VERSION 5.5 ;
NAMESCASESENSITIVE ON ;
BUSBITCHARS "[]" ;
DIVIDERCHAR "/" ;

PROPERTYDEFINITIONS
  LAYER routingPitch REAL ;
END PROPERTYDEFINITIONS

UNITS
  DATABASE MICRONS 1000 ;
END UNITS
MANUFACTURINGGRID 0.01 ;
LAYER POLY1
  TYPE MASTERSLICE ;
END POLY1

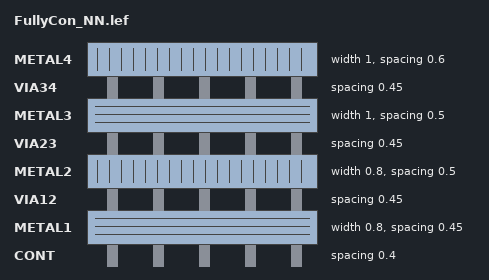
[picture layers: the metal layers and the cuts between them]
LAYER CONT
  TYPE CUT ;
  SPACING 0.4 ;
END CONT

LAYER METAL1
  TYPE ROUTING ;
  DIRECTION HORIZONTAL ;
  PITCH 0 ;
  WIDTH 0.8 ;
  SPACING 0.45 ;
  PROPERTY routingPitch 1.25 ;
END METAL1

LAYER VIA12
  TYPE CUT ;
  SPACING 0.45 ;
END VIA12

LAYER METAL2
  TYPE ROUTING ;
  DIRECTION VERTICAL ;
  PITCH 0 ;
  WIDTH 0.8 ;
  SPACING 0.5 ;
  PROPERTY routingPitch 1.4 ;
END METAL2

LAYER VIA23
  TYPE CUT ;
  SPACING 0.45 ;
END VIA23

LAYER METAL3
  TYPE ROUTING ;
  DIRECTION HORIZONTAL ;
  PITCH 0 ;
  WIDTH 1.0 ;
  SPACING 0.5 ;
  PROPERTY routingPitch 1.25 ;
END METAL3

LAYER VIA34
  TYPE CUT ;
  SPACING 0.45 ;
END VIA34

LAYER METAL4
  TYPE ROUTING ;
  DIRECTION VERTICAL ;
  PITCH 0 ;
  WIDTH 1.0 ;
  SPACING 0.6 ;
  PROPERTY routingPitch 1.4 ;
END METAL4

LAYER OVERLAP
  TYPE OVERLAP ;
END OVERLAP

VIARULE M4_M3 GENERATE
  LAYER METAL3 ;
    ENCLOSURE 0.2 0.2 ;
  LAYER METAL4 ;
    ENCLOSURE 0.15 0.15 ;
  LAYER VIA34 ;
    RECT -0.25 -0.25 0.25 0.25 ;
    SPACING 1 BY 1 ;
END M4_M3

VIARULE M3_M2 GENERATE
  LAYER METAL2 ;
    ENCLOSURE 0.2 0.2 ;
  LAYER METAL3 ;
    ENCLOSURE 0.15 0.15 ;
  LAYER VIA23 ;
    RECT -0.25 -0.25 0.25 0.25 ;
    SPACING 1 BY 1 ;
END M3_M2

VIARULE M2_M1 GENERATE
  LAYER METAL1 ;
    ENCLOSURE 0.2 0.2 ;
  LAYER METAL2 ;
    ENCLOSURE 0.15 0.15 ;
  LAYER VIA12 ;
    RECT -0.25 -0.25 0.25 0.25 ;
    SPACING 1 BY 1 ;
END M2_M1

VIARULE M1_POLY1 GENERATE
  LAYER POLY1 ;
    ENCLOSURE 0.2 0.2 ;
  LAYER METAL1 ;
    ENCLOSURE 0.15 0.15 ;
  LAYER CONT ;
    RECT -0.2 -0.2 0.2 0.2 ;
    SPACING 1 BY 1 ;
END M1_POLY1

VIA M1_POLY1
  LAYER CONT ;
    RECT -0.2 -0.2 0.2 0.2 ;
  LAYER POLY1 ;
    RECT -0.4 -0.4 0.4 0.4 ;
  LAYER METAL1 ;
    RECT -0.35 -0.35 0.35 0.35 ;
END M1_POLY1

VIA M2_M1
  LAYER VIA12 ;
    RECT -0.25 -0.25 0.25 0.25 ;
  LAYER METAL2 ;
    RECT -0.4 -0.4 0.4 0.4 ;
  LAYER METAL1 ;
    RECT -0.45 -0.45 0.45 0.45 ;
END M2_M1

VIA M3_M2
  LAYER VIA23 ;
    RECT -0.25 -0.25 0.25 0.25 ;
  LAYER METAL3 ;
    RECT -0.4 -0.4 0.4 0.4 ;
  LAYER METAL2 ;
    RECT -0.45 -0.45 0.45 0.45 ;
END M3_M2

VIA M4_M3
  LAYER VIA34 ;
    RECT -0.25 -0.25 0.25 0.25 ;
  LAYER METAL4 ;
    RECT -0.4 -0.4 0.4 0.4 ;
  LAYER METAL3 ;
    RECT -0.45 -0.45 0.45 0.45 ;
END M4_M3


MACRO TSMC350nm_VinjDecode2to4_vtile_spacing
END TSMC350nm_VinjDecode2to4_vtile_spacing

MACRO TSMC350nm_VinjDecode2to4_vtile_bridge_spacing
END TSMC350nm_VinjDecode2to4_vtile_bridge_spacing

MACRO TSMC350nm_VinjDecode2to4_vtile_D_bridge
END TSMC350nm_VinjDecode2to4_vtile_D_bridge

MACRO TSMC350nm_VinjDecode2to4_vtile
  PIN Vinj
    DIRECTION INOUT ;
    USE SIGNAL ;
    PORT
      LAYER METAL1 ;
        RECT 7.78 11.04 9.06 11.45 ;
    END
  END Vinj
  PIN OUT<0>
    DIRECTION INOUT ;
    USE SIGNAL ;
    PORT
      LAYER METAL1 ;
        RECT 19.66 18.91 20.11 19.59 ;
    END
  END OUT<0>
  PIN OUT<1>
    DIRECTION INOUT ;
    USE SIGNAL ;
    PORT
      LAYER METAL1 ;
        RECT 19.66 13.41 20.12 14.1 ;
    END
  END OUT<1>
  PIN OUT<2>
    DIRECTION INOUT ;
    USE SIGNAL ;
    PORT
      LAYER METAL1 ;
        RECT 19.66 7.92 20.11 8.59 ;
    END
  END OUT<2>
  PIN OUT<3>
    DIRECTION INOUT ;
    USE SIGNAL ;
    PORT
      LAYER METAL1 ;
        RECT 19.66 2.41 20.11 3.09 ;
    END
  END OUT<3>
  PIN ENABLE
    DIRECTION INOUT ;
    USE SIGNAL ;
    PORT
      LAYER METAL1 ;
        RECT 0.01 3.48 0.71 4.21 ;
    END
  END ENABLE
  PIN GND
    DIRECTION INOUT ;
    USE SIGNAL ;
    PORT
      LAYER METAL1 ;
        RECT 19.52 5.0 20.12 5.99 ;
    END
  END GND
  PIN VINJ
    DIRECTION INOUT ;
    USE SIGNAL ;
    PORT
      LAYER METAL1 ;
        RECT 19.15 21.56 20.05 21.96 ;
    END
  END VINJ
  PIN IN<1>
    DIRECTION INOUT ;
    USE SIGNAL ;
    PORT
      LAYER METAL2 ;
        RECT 6.56 20.89 7.5 22.0 ;
    END
  END IN<1>
  PIN IN<0>
    DIRECTION INOUT ;
    USE SIGNAL ;
    PORT
      LAYER METAL2 ;
        RECT 3.9 20.96 4.5 22.0 ;
    END
  END IN<0>
END TSMC350nm_VinjDecode2to4_vtile

MACRO TSMC350nm_VinjDecode2to4_vtile_C_bridge
END TSMC350nm_VinjDecode2to4_vtile_C_bridge

MACRO TSMC350nm_VinjDecode2to4_vtile_B_bridge
END TSMC350nm_VinjDecode2to4_vtile_B_bridge

MACRO TSMC350nm_VinjDecode2to4_vtile_A_bridge
END TSMC350nm_VinjDecode2to4_vtile_A_bridge

MACRO TSMC350nm_drainSelect_progrundrains
  PIN prog_drain<3>
    DIRECTION INOUT ;
    USE SIGNAL ;
    PORT
      LAYER METAL1 ;
        RECT 30.93 0.93 31.86 1.43 ;
    END
  END prog_drain<3>
  PIN prog_drain<2>
    DIRECTION INOUT ;
    USE SIGNAL ;
    PORT
      LAYER METAL1 ;
        RECT 30.97 9.62 31.86 10.12 ;
    END
  END prog_drain<2>
  PIN prog_drain<1>
    DIRECTION INOUT ;
    USE SIGNAL ;
    PORT
      LAYER METAL1 ;
        RECT 31.0 13.97 31.86 14.47 ;
    END
  END prog_drain<1>
  PIN run_drain<3>
    DIRECTION INOUT ;
    USE SIGNAL ;
    PORT
      LAYER METAL1 ;
        RECT 31.01 2.45 31.86 2.95 ;
    END
  END run_drain<3>
  PIN run_drain<2>
    DIRECTION INOUT ;
    USE SIGNAL ;
    PORT
      LAYER METAL1 ;
        RECT 30.94 5.31 31.86 5.81 ;
    END
  END run_drain<2>
  PIN prog_drain<0>
    DIRECTION INOUT ;
    USE SIGNAL ;
    PORT
      LAYER METAL1 ;
        RECT 31.12 20.75 31.86 21.25 ;
    END
  END prog_drain<0>
  PIN GND
    DIRECTION INOUT ;
    USE SIGNAL ;
    PORT
      LAYER METAL2 ;
        RECT 4.19 21.33 4.99 22.0 ;
    END
  END GND
  PIN VINJ
    DIRECTION INOUT ;
    USE SIGNAL ;
    PORT
      LAYER METAL1 ;
        RECT 1.4 21.5 2.8 22.0 ;
    END
  END VINJ
  PIN run_drain<0>
    DIRECTION INOUT ;
    USE SIGNAL ;
    PORT
      LAYER METAL1 ;
        RECT 31.01 19.56 31.86 20.06 ;
    END
  END run_drain<0>
  PIN run_drain<1>
    DIRECTION INOUT ;
    USE SIGNAL ;
    PORT
      LAYER METAL1 ;
        RECT 31.04 16.75 31.86 17.24 ;
    END
  END run_drain<1>
  PIN SELECT<3>
    DIRECTION INOUT ;
    USE SIGNAL ;
    PORT
      LAYER METAL1 ;
        RECT 0.0 2.54 0.67 2.97 ;
    END
  END SELECT<3>
  PIN SELET<2>
    DIRECTION INOUT ;
    USE SIGNAL ;
    PORT
      LAYER METAL1 ;
        RECT 0.0 8.03 0.67 8.46 ;
    END
  END SELET<2>
  PIN SELECT<1>
    DIRECTION INOUT ;
    USE SIGNAL ;
    PORT
      LAYER METAL1 ;
        RECT 0.0 13.54 0.67 13.97 ;
    END
  END SELECT<1>
  PIN SELECT<0>
    DIRECTION INOUT ;
    USE SIGNAL ;
    PORT
      LAYER METAL1 ;
        RECT 0.0 18.9 0.67 19.6 ;
    END
  END SELECT<0>
  PIN VINJ_b
    DIRECTION INOUT ;
    USE SIGNAL ;
    PORT
      LAYER METAL2 ;
        RECT 21.94 0.0 23.29 0.58 ;
    END
  END VINJ_b
  PIN GND_b
    DIRECTION INOUT ;
    USE SIGNAL ;
    PORT
      LAYER METAL2 ;
        RECT 17.16 0.0 18.16 0.58 ;
    END
  END GND_b
  PIN run_drainrail
    DIRECTION INOUT ;
    USE SIGNAL ;
    PORT
      LAYER METAL2 ;
        RECT 27.01 21.19 27.71 22.0 ;
    END
  END run_drainrail
  PIN prog_drainrail
    DIRECTION INOUT ;
    USE SIGNAL ;
    PORT
      LAYER METAL2 ;
        RECT 7.36 21.34 8.16 22.0 ;
    END
  END prog_drainrail
END TSMC350nm_drainSelect_progrundrains

MACRO TSMC350nm_4TGate_ST_draincutoff
  PIN In<0>
    DIRECTION INOUT ;
    USE SIGNAL ;
    PORT
      LAYER METAL1 ;
        RECT 9.96 17.5 10.6 18.45 ;
    END
  END In<0>
  PIN In<1>
    DIRECTION INOUT ;
    USE SIGNAL ;
    PORT
      LAYER METAL1 ;
        RECT 9.91 14.7 10.6 15.93 ;
    END
  END In<1>
  PIN In<2>
    DIRECTION INOUT ;
    USE SIGNAL ;
    PORT
      LAYER METAL1 ;
        RECT 10.01 6.9 10.6 7.8 ;
    END
  END In<2>
  PIN In<3>
    DIRECTION INOUT ;
    USE SIGNAL ;
    PORT
      LAYER METAL1 ;
        RECT 10.02 3.5 10.6 4.3 ;
    END
  END In<3>
  PIN A<0>
    DIRECTION INOUT ;
    USE SIGNAL ;
    PORT
      LAYER METAL1 ;
        RECT 0.0 19.56 1.4 20.06 ;
    END
  END A<0>
  PIN A<1>
    DIRECTION INOUT ;
    USE SIGNAL ;
    PORT
      LAYER METAL1 ;
        RECT 0.0 16.75 1.4 17.25 ;
    END
  END A<1>
  PIN A<2>
    DIRECTION INOUT ;
    USE SIGNAL ;
    PORT
      LAYER METAL1 ;
        RECT 0.0 5.3 1.4 5.8 ;
    END
  END A<2>
  PIN A<3>
    DIRECTION INOUT ;
    USE SIGNAL ;
    PORT
      LAYER METAL1 ;
        RECT 0.0 2.45 1.4 2.95 ;
    END
  END A<3>
  PIN P<0>
    DIRECTION INOUT ;
    USE SIGNAL ;
    PORT
      LAYER METAL1 ;
        RECT 0.0 20.75 1.4 21.25 ;
    END
  END P<0>
  PIN P<1>
    DIRECTION INOUT ;
    USE SIGNAL ;
    PORT
      LAYER METAL1 ;
        RECT 0.0 13.97 1.4 14.47 ;
    END
  END P<1>
  PIN P<2>
    DIRECTION INOUT ;
    USE SIGNAL ;
    PORT
      LAYER METAL1 ;
        RECT 0.0 9.62 1.4 10.12 ;
    END
  END P<2>
  PIN P<3>
    DIRECTION INOUT ;
    USE SIGNAL ;
    PORT
      LAYER METAL1 ;
        RECT 0.0 0.93 1.4 1.43 ;
    END
  END P<3>
  PIN PR<0>
    DIRECTION INOUT ;
    USE SIGNAL ;
    PORT
      LAYER METAL1 ;
        RECT 10.0 20.3 10.6 21.25 ;
    END
  END PR<0>
  PIN PR<1>
    DIRECTION INOUT ;
    USE SIGNAL ;
    PORT
      LAYER METAL1 ;
        RECT 10.13 11.9 10.6 12.8 ;
    END
  END PR<1>
  PIN PR<2>
    DIRECTION INOUT ;
    USE SIGNAL ;
    PORT
      LAYER METAL1 ;
        RECT 10.0 9.4 10.6 10.3 ;
    END
  END PR<2>
  PIN PR<3>
    DIRECTION INOUT ;
    USE SIGNAL ;
    PORT
      LAYER METAL1 ;
        RECT 10.0 0.7 10.6 1.6 ;
    END
  END PR<3>
  PIN VDD_b
    DIRECTION INOUT ;
    USE SIGNAL ;
    PORT
      LAYER METAL2 ;
        RECT 7.89 0.0 8.79 0.54 ;
    END
  END VDD_b
  PIN RUN
    DIRECTION INOUT ;
    USE SIGNAL ;
    PORT
      LAYER METAL2 ;
        RECT 5.9 21.13 6.5 22.0 ;
    END
  END RUN
  PIN VDD
    DIRECTION INOUT ;
    USE SIGNAL ;
    PORT
      LAYER METAL2 ;
        RECT 7.89 21.3 8.79 22.0 ;
    END
  END VDD
  PIN GND
    DIRECTION INOUT ;
    USE SIGNAL ;
    PORT
      LAYER METAL2 ;
        RECT 3.35 21.3 4.25 22.0 ;
    END
  END GND
  PIN GND_b
    DIRECTION INOUT ;
    USE SIGNAL ;
    PORT
      LAYER METAL2 ;
        RECT 3.35 0.0 4.25 0.73 ;
    END
  END GND_b
  PIN RUN_b
    DIRECTION INOUT ;
    USE SIGNAL ;
    PORT
      LAYER METAL2 ;
        RECT 5.9 0.0 6.5 0.71 ;
    END
  END RUN_b
END TSMC350nm_4TGate_ST_draincutoff

MACRO TSMC350nm_IndirectSwitches
  PIN GND_B<1>
    DIRECTION INOUT ;
    USE SIGNAL ;
    PORT
      LAYER METAL2 ;
        RECT 15.41 0.0 16.01 0.85 ;
    END
  END GND_B<1>
  PIN GND_B<0>
    DIRECTION INOUT ;
    USE SIGNAL ;
    PORT
      LAYER METAL2 ;
        RECT 11.2 0.0 11.8 0.85 ;
    END
  END GND_B<0>
  PIN GND
    DIRECTION INOUT ;
    USE SIGNAL ;
    PORT
      LAYER METAL2 ;
        RECT 11.2 3.21 11.8 3.6 ;
    END
  END GND
  PIN GND_T
    DIRECTION INOUT ;
    USE SIGNAL ;
    PORT
      LAYER METAL2 ;
        RECT 15.4 21.0 16.2 22.0 ;
    END
  END GND_T
  PIN VINJ_T
    DIRECTION INOUT ;
    USE SIGNAL ;
    PORT
      LAYER METAL2 ;
        RECT 6.3 21.04 7.32 22.0 ;
    END
  END VINJ_T
  PIN VDD<1>
    DIRECTION INOUT ;
    USE SIGNAL ;
    PORT
      LAYER METAL2 ;
        RECT 24.5 0.0 25.1 0.75 ;
    END
  END VDD<1>
  PIN VTUN
    DIRECTION INOUT ;
    USE SIGNAL ;
    PORT
      LAYER METAL2 ;
        RECT 13.3 0.0 13.9 0.82 ;
    END
  END VTUN
  PIN VINJ
    DIRECTION INOUT ;
    USE SIGNAL ;
    PORT
      LAYER METAL2 ;
        RECT 4.2 0.0 4.8 1.0 ;
    END
  END VINJ
  PIN VDD<0>
    DIRECTION INOUT ;
    USE SIGNAL ;
    PORT
      LAYER METAL2 ;
        RECT 2.1 0.0 2.7 1.09 ;
    END
  END VDD<0>
  PIN Vg<0>
    DIRECTION INOUT ;
    USE SIGNAL ;
    PORT
      LAYER METAL2 ;
        RECT 8.4 0.005 9.0 0.825 ;
    END
  END Vg<0>
  PIN CTRL_B<0>
    DIRECTION INOUT ;
    USE SIGNAL ;
    PORT
      LAYER METAL2 ;
        RECT 6.3 0.01 6.9 0.76 ;
    END
  END CTRL_B<0>
  PIN CTRL_B<1>
    DIRECTION INOUT ;
    USE SIGNAL ;
    PORT
      LAYER METAL2 ;
        RECT 20.3 0.01 20.9 0.75 ;
    END
  END CTRL_B<1>
  PIN Vg<1>
    DIRECTION INOUT ;
    USE SIGNAL ;
    PORT
      LAYER METAL2 ;
        RECT 18.2 0.0 18.8 0.76 ;
    END
  END Vg<1>
  PIN decode<0>
    DIRECTION INOUT ;
    USE SIGNAL ;
    PORT
      LAYER METAL2 ;
        RECT 3.46 21.16 4.8 22.0 ;
    END
  END decode<0>
  PIN RUN_IN<1>
    DIRECTION INOUT ;
    USE SIGNAL ;
    PORT
      LAYER METAL2 ;
        RECT 17.5 21.01 18.1 22.0 ;
    END
  END RUN_IN<1>
  PIN RUN_IN<0>
    DIRECTION INOUT ;
    USE SIGNAL ;
    PORT
      LAYER METAL2 ;
        RECT 10.5 20.9 11.1 22.0 ;
    END
  END RUN_IN<0>
  PIN VPWR<1>
    DIRECTION INOUT ;
    USE SIGNAL ;
    PORT
      LAYER METAL2 ;
        RECT 21.7 21.08 22.3 22.0 ;
    END
  END VPWR<1>
  PIN decode<1>
    DIRECTION INOUT ;
    USE SIGNAL ;
    PORT
      LAYER METAL2 ;
        RECT 23.8 21.09 25.0 22.0 ;
    END
  END decode<1>
  PIN VPWR<0>
    DIRECTION INOUT ;
    USE SIGNAL ;
    PORT
      LAYER METAL2 ;
        RECT 1.71 21.21 2.43 22.0 ;
    END
  END VPWR<0>
  PIN VTUN_T
    DIRECTION INOUT ;
    USE SIGNAL ;
    PORT
      LAYER METAL2 ;
        RECT 12.6 21.12 13.7 22.0 ;
    END
  END VTUN_T
  PIN vtun_r
    DIRECTION INOUT ;
    USE SIGNAL ;
    PORT
      LAYER METAL1 ;
        RECT 26.17 0.9 27.46 2.17 ;
    END
  END vtun_r
  PIN vgsel_r
    DIRECTION INOUT ;
    USE SIGNAL ;
    PORT
      LAYER METAL1 ;
        RECT 26.52 3.15 27.46 4.45 ;
    END
  END vgsel_r
  PIN prog_r
    DIRECTION INOUT ;
    USE SIGNAL ;
    PORT
      LAYER METAL1 ;
        RECT 26.59 9.15 27.46 10.55 ;
    END
  END prog_r
  PIN run_r
    DIRECTION INOUT ;
    USE SIGNAL ;
    PORT
      LAYER METAL1 ;
        RECT 26.28 6.05 27.46 7.29 ;
    END
  END run_r
  PIN RUN
    DIRECTION INOUT ;
    USE SIGNAL ;
    PORT
      LAYER METAL1 ;
        RECT 0.0 6.05 0.91 7.29 ;
    END
  END RUN
  PIN PROG
    DIRECTION INOUT ;
    USE SIGNAL ;
    PORT
      LAYER METAL1 ;
        RECT 0.0 9.15 0.87 10.55 ;
    END
  END PROG
  PIN Vgsel
    DIRECTION INOUT ;
    USE SIGNAL ;
    PORT
      LAYER METAL1 ;
        RECT 0.0 3.72 0.91 4.45 ;
    END
  END Vgsel
  PIN vtun_l
    DIRECTION INOUT ;
    USE SIGNAL ;
    PORT
      LAYER METAL1 ;
        RECT 0.0 0.9 1.31 1.88 ;
    END
  END vtun_l
END TSMC350nm_IndirectSwitches

MACRO TSMC350nm_VinjDecode2to4_htile
  PIN IN<1>
    DIRECTION INOUT ;
    USE SIGNAL ;
    PORT
      LAYER METAL1 ;
        RECT 0.0 11.85 0.9 12.74 ;
    END
  END IN<1>
  PIN IN<0>
    DIRECTION INOUT ;
    USE SIGNAL ;
    PORT
      LAYER METAL1 ;
        RECT 0.0 10.13 0.87 11.1 ;
    END
  END IN<0>
  PIN VINJ
    DIRECTION INOUT ;
    USE SIGNAL ;
    PORT
      LAYER METAL1 ;
        RECT 0.0 1.99 0.5 2.49 ;
    END
  END VINJ
  PIN GND
    DIRECTION INOUT ;
    USE SIGNAL ;
    PORT
      LAYER METAL1 ;
        RECT 0.0 6.99 0.51 7.49 ;
    END
  END GND
  PIN GND_b<1>
    DIRECTION INOUT ;
    USE SIGNAL ;
    PORT
      LAYER METAL2 ;
        RECT 40.32 0.0 40.92 1.79 ;
    END
  END GND_b<1>
  PIN VINJ_b<1>
    DIRECTION INOUT ;
    USE SIGNAL ;
    PORT
      LAYER METAL2 ;
        RECT 22.1 0.0 22.7 1.44 ;
    END
  END VINJ_b<1>
  PIN GND_b<0>
    DIRECTION INOUT ;
    USE SIGNAL ;
    PORT
      LAYER METAL2 ;
        RECT 18.85 0.0 19.45 1.41 ;
    END
  END GND_b<0>
  PIN VINJ_b<0>
    DIRECTION INOUT ;
    USE SIGNAL ;
    PORT
      LAYER METAL2 ;
        RECT 1.07 0.0 1.67 1.25 ;
    END
  END VINJ_b<0>
  PIN VINJV
    DIRECTION INOUT ;
    USE SIGNAL ;
    PORT
      LAYER METAL2 ;
        RECT 23.7 21.26 24.31 22.0 ;
    END
  END VINJV
  PIN GNDV
    DIRECTION INOUT ;
    USE SIGNAL ;
    PORT
      LAYER METAL2 ;
        RECT 25.84 21.28 26.44 22.0 ;
    END
  END GNDV
  PIN RUN_OUT<3>
    DIRECTION INOUT ;
    USE SIGNAL ;
    PORT
      LAYER METAL2 ;
        RECT 34.39 0.0 35.19 0.86 ;
    END
  END RUN_OUT<3>
  PIN RUN_OUT<2>
    DIRECTION INOUT ;
    USE SIGNAL ;
    PORT
      LAYER METAL2 ;
        RECT 28.77 0.0 29.57 0.86 ;
    END
  END RUN_OUT<2>
  PIN RUN_OUT<1>
    DIRECTION INOUT ;
    USE SIGNAL ;
    PORT
      LAYER METAL2 ;
        RECT 13.5 0.0 14.1 0.86 ;
    END
  END RUN_OUT<1>
  PIN RUN_OUT<0>
    DIRECTION INOUT ;
    USE SIGNAL ;
    PORT
      LAYER METAL2 ;
        RECT 7.34 0.0 8.14 0.86 ;
    END
  END RUN_OUT<0>
  PIN ENABLE
    DIRECTION INOUT ;
    USE SIGNAL ;
    PORT
      LAYER METAL2 ;
        RECT 6.29 21.66 6.89 22.0 ;
    END
  END ENABLE
  PIN OUT<2>
    DIRECTION INOUT ;
    USE SIGNAL ;
    PORT
      LAYER METAL2 ;
        RECT 25.28 0.0 25.87 0.87 ;
    END
  END OUT<2>
  PIN OUT<3>
    DIRECTION INOUT ;
    USE SIGNAL ;
    PORT
      LAYER METAL2 ;
        RECT 37.14 0.0 37.73 0.83 ;
    END
  END OUT<3>
  PIN OUT<0>
    DIRECTION INOUT ;
    USE SIGNAL ;
    PORT
      LAYER METAL2 ;
        RECT 4.27 0.0 4.87 0.86 ;
    END
  END OUT<0>
  PIN OUT<1>
    DIRECTION INOUT ;
    USE SIGNAL ;
    PORT
      LAYER METAL2 ;
        RECT 16.14 0.0 16.72 0.85 ;
    END
  END OUT<1>
  PIN VGRUN<0>
    DIRECTION INOUT ;
    USE SIGNAL ;
    PORT
      LAYER METAL2 ;
        RECT 9.1 21.59 9.7 22.0 ;
    END
  END VGRUN<0>
  PIN VGRUN<1>
    DIRECTION INOUT ;
    USE SIGNAL ;
    PORT
      LAYER METAL2 ;
        RECT 11.2 21.6 11.8 22.0 ;
    END
  END VGRUN<1>
  PIN VGRUN<2>
    DIRECTION INOUT ;
    USE SIGNAL ;
    PORT
      LAYER METAL2 ;
        RECT 28.7 21.71 29.3 22.0 ;
    END
  END VGRUN<2>
  PIN VGRUN<3>
    DIRECTION INOUT ;
    USE SIGNAL ;
    PORT
      LAYER METAL2 ;
        RECT 33.6 21.54 34.2 22.0 ;
    END
  END VGRUN<3>
END TSMC350nm_VinjDecode2to4_htile

MACRO TSMC350nm_VinjDecode2to4_htile_A_bridge
  PIN VGRUN<3>
    DIRECTION INOUT ;
    USE SIGNAL ;
    PORT
      LAYER METAL2 ;
        RECT 34.5 9.46 35.1 10.0 ;
    END
  END VGRUN<3>
  PIN VGRUN<2>
    DIRECTION INOUT ;
    USE SIGNAL ;
    PORT
      LAYER METAL2 ;
        RECT 26.6 9.56 27.2 10.0 ;
    END
  END VGRUN<2>
  PIN VGRUN<1>
    DIRECTION INOUT ;
    USE SIGNAL ;
    PORT
      LAYER METAL2 ;
        RECT 13.5 9.46 14.1 10.0 ;
    END
  END VGRUN<1>
  PIN VGRUN<0>
    DIRECTION INOUT ;
    USE SIGNAL ;
    PORT
      LAYER METAL2 ;
        RECT 5.6 9.52 6.2 10.0 ;
    END
  END VGRUN<0>
END TSMC350nm_VinjDecode2to4_htile_A_bridge

MACRO TSMC350nm_VinjDecode2to4_htile_B_bridge
  PIN VGRUN<0>
    DIRECTION INOUT ;
    USE SIGNAL ;
    PORT
      LAYER METAL2 ;
        RECT 9.1 9.52 9.7 10.0 ;
    END
  END VGRUN<0>
  PIN VGRUN<1>
    DIRECTION INOUT ;
    USE SIGNAL ;
    PORT
      LAYER METAL2 ;
        RECT 11.2 9.52 11.8 10.0 ;
    END
  END VGRUN<1>
  PIN VGRUN<2>
    DIRECTION INOUT ;
    USE SIGNAL ;
    PORT
      LAYER METAL2 ;
        RECT 28.7 9.5 29.3 10.0 ;
    END
  END VGRUN<2>
  PIN VGRUN<3>
    DIRECTION INOUT ;
    USE SIGNAL ;
    PORT
      LAYER METAL2 ;
        RECT 33.6 9.51 34.2 10.0 ;
    END
  END VGRUN<3>
END TSMC350nm_VinjDecode2to4_htile_B_bridge

MACRO TSMC350nm_VinjDecode2to4_htile_C_bridge
  PIN VGRUN<0>
    DIRECTION INOUT ;
    USE SIGNAL ;
    PORT
      LAYER METAL2 ;
        RECT 9.1 9.54 9.7 10.0 ;
    END
  END VGRUN<0>
  PIN VGRUN<1>
    DIRECTION INOUT ;
    USE SIGNAL ;
    PORT
      LAYER METAL2 ;
        RECT 11.2 9.57 11.8 10.0 ;
    END
  END VGRUN<1>
  PIN VGRUN<2>
    DIRECTION INOUT ;
    USE SIGNAL ;
    PORT
      LAYER METAL2 ;
        RECT 28.7 9.59 29.3 10.0 ;
    END
  END VGRUN<2>
  PIN VGRUN<3>
    DIRECTION INOUT ;
    USE SIGNAL ;
    PORT
      LAYER METAL2 ;
        RECT 33.6 9.57 34.2 10.0 ;
    END
  END VGRUN<3>
END TSMC350nm_VinjDecode2to4_htile_C_bridge

MACRO TSMC350nm_VinjDecode2to4_htile_D_bridge
  PIN VGRUN<0>
    DIRECTION INOUT ;
    USE SIGNAL ;
    PORT
      LAYER METAL2 ;
        RECT 9.1 9.58 9.7 10.0 ;
    END
  END VGRUN<0>
  PIN VGRUN<1>
    DIRECTION INOUT ;
    USE SIGNAL ;
    PORT
      LAYER METAL2 ;
        RECT 11.2 9.55 11.8 10.0 ;
    END
  END VGRUN<1>
  PIN VGRUN<2>
    DIRECTION INOUT ;
    USE SIGNAL ;
    PORT
      LAYER METAL2 ;
        RECT 28.7 9.58 29.3 10.0 ;
    END
  END VGRUN<2>
  PIN VGRUN<3>
    DIRECTION INOUT ;
    USE SIGNAL ;
    PORT
      LAYER METAL2 ;
        RECT 33.6 9.57 34.2 10.0 ;
    END
  END VGRUN<3>
END TSMC350nm_VinjDecode2to4_htile_D_bridge

MACRO TSMC350nm_VinjDecode2to4_htile_spacing
  PIN VGRUN<0>
    DIRECTION INOUT ;
    USE SIGNAL ;
    PORT
      LAYER METAL2 ;
        RECT 9.1 21.59 9.7 22.0 ;
    END
  END VGRUN<0>
  PIN VGRUN<1>
    DIRECTION INOUT ;
    USE SIGNAL ;
    PORT
      LAYER METAL2 ;
        RECT 11.2 21.52 11.8 22.0 ;
    END
  END VGRUN<1>
  PIN VGRUN<2>
    DIRECTION INOUT ;
    USE SIGNAL ;
    PORT
      LAYER METAL2 ;
        RECT 28.7 21.54 29.3 22.0 ;
    END
  END VGRUN<2>
  PIN VGRUN<3>
    DIRECTION INOUT ;
    USE SIGNAL ;
    PORT
      LAYER METAL2 ;
        RECT 33.6 21.55 34.2 22.0 ;
    END
  END VGRUN<3>
END TSMC350nm_VinjDecode2to4_htile_spacing

MACRO TSMC350nm_VinjDecode2to4_htile_bridge_spacing
  PIN VGRUN<0>
    DIRECTION INOUT ;
    USE SIGNAL ;
    PORT
      LAYER METAL2 ;
        RECT 9.1 9.52 9.7 9.99 ;
    END
  END VGRUN<0>
  PIN VGRUN<1>
    DIRECTION INOUT ;
    USE SIGNAL ;
    PORT
      LAYER METAL2 ;
        RECT 11.2 9.51 11.8 9.99 ;
    END
  END VGRUN<1>
  PIN VGRUN<2>
    DIRECTION INOUT ;
    USE SIGNAL ;
    PORT
      LAYER METAL2 ;
        RECT 28.7 9.41 29.3 9.99 ;
    END
  END VGRUN<2>
  PIN VGRUN<3>
    DIRECTION INOUT ;
    USE SIGNAL ;
    PORT
      LAYER METAL2 ;
        RECT 33.6 9.47 34.2 9.99 ;
    END
  END VGRUN<3>
END TSMC350nm_VinjDecode2to4_htile_bridge_spacing

MACRO TSMC350nm_4TGate_ST_BMatrix
  PIN In<0>
    DIRECTION INOUT ;
    USE SIGNAL ;
    PORT
      LAYER METAL1 ;
        RECT 0.0 17.5 0.27 18.0 ;
    END
  END In<0>
  PIN In<1>
    DIRECTION INOUT ;
    USE SIGNAL ;
    PORT
      LAYER METAL1 ;
        RECT 0.0 14.7 0.38 15.2 ;
    END
  END In<1>
  PIN In<2>
    DIRECTION INOUT ;
    USE SIGNAL ;
    PORT
      LAYER METAL1 ;
        RECT 0.0 7.0 0.36 7.5 ;
    END
  END In<2>
  PIN In<3>
    DIRECTION INOUT ;
    USE SIGNAL ;
    PORT
      LAYER METAL1 ;
        RECT 0.0 3.5 0.3 4.0 ;
    END
  END In<3>
  PIN A<0>
    DIRECTION INOUT ;
    USE SIGNAL ;
    PORT
      LAYER METAL1 ;
        RECT 10.6 17.6 12.0 18.9 ;
    END
  END A<0>
  PIN A<1>
    DIRECTION INOUT ;
    USE SIGNAL ;
    PORT
      LAYER METAL1 ;
        RECT 10.6 14.9 12.0 16.2 ;
    END
  END A<1>
  PIN A<2>
    DIRECTION INOUT ;
    USE SIGNAL ;
    PORT
      LAYER METAL1 ;
        RECT 10.6 6.8 12.0 8.1 ;
    END
  END A<2>
  PIN A<3>
    DIRECTION INOUT ;
    USE SIGNAL ;
    PORT
      LAYER METAL1 ;
        RECT 10.6 4.1 12.0 5.4 ;
    END
  END A<3>
  PIN P<0>
    DIRECTION INOUT ;
    USE SIGNAL ;
    PORT
      LAYER METAL1 ;
        RECT 10.6 20.3 12.0 21.6 ;
    END
  END P<0>
  PIN P<1>
    DIRECTION INOUT ;
    USE SIGNAL ;
    PORT
      LAYER METAL1 ;
        RECT 10.6 12.2 12.0 13.5 ;
    END
  END P<1>
  PIN P<2>
    DIRECTION INOUT ;
    USE SIGNAL ;
    PORT
      LAYER METAL1 ;
        RECT 10.6 9.5 12.0 10.8 ;
    END
  END P<2>
  PIN P<3>
    DIRECTION INOUT ;
    USE SIGNAL ;
    PORT
      LAYER METAL1 ;
        RECT 10.6 1.4 12.0 2.7 ;
    END
  END P<3>
  PIN GND_b
    DIRECTION INOUT ;
    USE SIGNAL ;
    PORT
      LAYER METAL2 ;
        RECT 6.35 0.0 7.25 0.88 ;
    END
  END GND_b
  PIN Prog_b
    DIRECTION INOUT ;
    USE SIGNAL ;
    PORT
      LAYER METAL2 ;
        RECT 4.1 0.0 4.7 0.78 ;
    END
  END Prog_b
  PIN VDD_b
    DIRECTION INOUT ;
    USE SIGNAL ;
    PORT
      LAYER METAL2 ;
        RECT 1.81 0.0 2.71 0.71 ;
    END
  END VDD_b
  PIN Prog
    DIRECTION INOUT ;
    USE SIGNAL ;
    PORT
      LAYER METAL2 ;
        RECT 4.1 21.3 4.7 22.0 ;
    END
  END Prog
  PIN VDD
    DIRECTION INOUT ;
    USE SIGNAL ;
    PORT
      LAYER METAL2 ;
        RECT 1.81 21.3 2.71 22.0 ;
    END
  END VDD
  PIN GND
    DIRECTION INOUT ;
    USE SIGNAL ;
    PORT
      LAYER METAL2 ;
        RECT 6.35 21.3 7.25 22.0 ;
    END
  END GND
END TSMC350nm_4TGate_ST_BMatrix

MACRO TSMC350nm_VerticalScanner_STD
  PIN In<3>
    DIRECTION INOUT ;
    USE SIGNAL ;
    PORT
      LAYER METAL1 ;
        RECT 0.0 3.5 1.4 4.9 ;
    END
  END In<3>
  PIN In<2>
    DIRECTION INOUT ;
    USE SIGNAL ;
    PORT
      LAYER METAL1 ;
        RECT 0.0 6.3 1.5 7.7 ;
    END
  END In<2>
  PIN In<1>
    DIRECTION INOUT ;
    USE SIGNAL ;
    PORT
      LAYER METAL1 ;
        RECT 0.0 14.0 1.4 15.4 ;
    END
  END In<1>
  PIN In<0>
    DIRECTION INOUT ;
    USE SIGNAL ;
    PORT
      LAYER METAL1 ;
        RECT 0.0 17.5 1.4 18.9 ;
    END
  END In<0>
  PIN RSTBar_b
    DIRECTION INOUT ;
    USE SIGNAL ;
    PORT
      LAYER METAL2 ;
        RECT 156.1 0.0 157.5 1.23 ;
    END
  END RSTBar_b
  PIN CLK_b
    DIRECTION INOUT ;
    USE SIGNAL ;
    PORT
      LAYER METAL2 ;
        RECT 149.8 0.0 151.2 1.23 ;
    END
  END CLK_b
  PIN Out
    DIRECTION INOUT ;
    USE SIGNAL ;
    PORT
      LAYER METAL2 ;
        RECT 5.15 20.68 6.65 22.0 ;
    END
  END Out
  PIN Out_b
    DIRECTION INOUT ;
    USE SIGNAL ;
    PORT
      LAYER METAL2 ;
        RECT 5.15 0.0 6.65 1.27 ;
    END
  END Out_b
  PIN VDD_b
    DIRECTION INOUT ;
    USE SIGNAL ;
    PORT
      LAYER METAL2 ;
        RECT 45.86 0.0 47.36 1.28 ;
    END
  END VDD_b
  PIN GND_b
    DIRECTION INOUT ;
    USE SIGNAL ;
    PORT
      LAYER METAL2 ;
        RECT 53.79 0.0 55.29 1.23 ;
    END
  END GND_b
  PIN VDD
    DIRECTION INOUT ;
    USE SIGNAL ;
    PORT
      LAYER METAL2 ;
        RECT 45.86 20.77 47.36 22.0 ;
    END
  END VDD
  PIN GND
    DIRECTION INOUT ;
    USE SIGNAL ;
    PORT
      LAYER METAL2 ;
        RECT 53.79 20.84 55.29 22.0 ;
    END
  END GND
  PIN Din
    DIRECTION INOUT ;
    USE SIGNAL ;
    PORT
      LAYER METAL2 ;
        RECT 42.0 20.77 43.4 22.0 ;
    END
  END Din
  PIN Qout
    DIRECTION INOUT ;
    USE SIGNAL ;
    PORT
      LAYER METAL2 ;
        RECT 42.0 0.0 43.4 1.23 ;
    END
  END Qout
  PIN RSTBar
    DIRECTION INOUT ;
    USE SIGNAL ;
    PORT
      LAYER METAL2 ;
        RECT 156.1 20.77 157.5 22.0 ;
    END
  END RSTBar
  PIN CLK
    DIRECTION INOUT ;
    USE SIGNAL ;
    PORT
      LAYER METAL2 ;
        RECT 149.8 20.77 151.2 22.0 ;
    END
  END CLK
END TSMC350nm_VerticalScanner_STD

MACRO TSMC350nm_4x2_Indirect
  PIN Vg<1>
    DIRECTION INOUT ;
    USE SIGNAL ;
    PORT
      LAYER METAL2 ;
        RECT 18.2 21.06 18.8 22.0 ;
    END
  END Vg<1>
  PIN Vsel<1>
    DIRECTION INOUT ;
    USE SIGNAL ;
    PORT
      LAYER METAL2 ;
        RECT 20.3 21.08 20.9 22.0 ;
    END
  END Vsel<1>
  PIN VINJ<1>
    DIRECTION INOUT ;
    USE SIGNAL ;
    PORT
      LAYER METAL2 ;
        RECT 22.4 21.05 23.0 22.0 ;
    END
  END VINJ<1>
  PIN Vsel<0>
    DIRECTION INOUT ;
    USE SIGNAL ;
    PORT
      LAYER METAL2 ;
        RECT 6.3 21.2 6.9 22.0 ;
    END
  END Vsel<0>
  PIN Vs<0>
    DIRECTION INOUT ;
    USE SIGNAL ;
    PORT
      LAYER METAL2 ;
        RECT 2.1 21.21 2.7 22.0 ;
    END
  END Vs<0>
  PIN Vs<1>
    DIRECTION INOUT ;
    USE SIGNAL ;
    PORT
      LAYER METAL2 ;
        RECT 24.5 21.06 25.1 22.0 ;
    END
  END Vs<1>
  PIN VTUN
    DIRECTION INOUT ;
    USE SIGNAL ;
    PORT
      LAYER METAL2 ;
        RECT 13.3 21.09 13.9 22.0 ;
    END
  END VTUN
  PIN VINJ<0>
    DIRECTION INOUT ;
    USE SIGNAL ;
    PORT
      LAYER METAL2 ;
        RECT 4.2 21.18 4.8 22.0 ;
    END
  END VINJ<0>
  PIN GND<0>
    DIRECTION INOUT ;
    USE SIGNAL ;
    PORT
      LAYER METAL2 ;
        RECT 11.2 21.07 11.8 22.0 ;
    END
  END GND<0>
  PIN Vg<0>
    DIRECTION INOUT ;
    USE SIGNAL ;
    PORT
      LAYER METAL2 ;
        RECT 8.4 21.03 9.0 22.0 ;
    END
  END Vg<0>
  PIN GND<1>
    DIRECTION INOUT ;
    USE SIGNAL ;
    PORT
      LAYER METAL2 ;
        RECT 15.41 21.06 16.01 22.0 ;
    END
  END GND<1>
  PIN Vs_b<0>
    DIRECTION INOUT ;
    USE SIGNAL ;
    PORT
      LAYER METAL2 ;
        RECT 1.42 0.0 2.7 0.6 ;
    END
  END Vs_b<0>
  PIN VINJ_b<0>
    DIRECTION INOUT ;
    USE SIGNAL ;
    PORT
      LAYER METAL2 ;
        RECT 4.2 0.0 4.8 0.76 ;
    END
  END VINJ_b<0>
  PIN Vsel_b<0>
    DIRECTION INOUT ;
    USE SIGNAL ;
    PORT
      LAYER METAL2 ;
        RECT 6.3 0.0 6.9 0.78 ;
    END
  END Vsel_b<0>
  PIN Vg_b<0>
    DIRECTION INOUT ;
    USE SIGNAL ;
    PORT
      LAYER METAL2 ;
        RECT 8.4 0.0 9.0 0.77 ;
    END
  END Vg_b<0>
  PIN GND_b<0>
    DIRECTION INOUT ;
    USE SIGNAL ;
    PORT
      LAYER METAL2 ;
        RECT 11.2 0.0 11.8 0.76 ;
    END
  END GND_b<0>
  PIN VTUN_b
    DIRECTION INOUT ;
    USE SIGNAL ;
    PORT
      LAYER METAL2 ;
        RECT 13.3 0.0 13.9 0.76 ;
    END
  END VTUN_b
  PIN GND_b<1>
    DIRECTION INOUT ;
    USE SIGNAL ;
    PORT
      LAYER METAL2 ;
        RECT 15.41 0.0 16.01 0.83 ;
    END
  END GND_b<1>
  PIN Vg_b<1>
    DIRECTION INOUT ;
    USE SIGNAL ;
    PORT
      LAYER METAL2 ;
        RECT 18.2 0.0 18.8 0.76 ;
    END
  END Vg_b<1>
  PIN Vsel_b<1>
    DIRECTION INOUT ;
    USE SIGNAL ;
    PORT
      LAYER METAL2 ;
        RECT 20.3 0.0 20.9 0.75 ;
    END
  END Vsel_b<1>
  PIN VINJ_b<1>
    DIRECTION INOUT ;
    USE SIGNAL ;
    PORT
      LAYER METAL2 ;
        RECT 22.4 0.0 23.0 0.77 ;
    END
  END VINJ_b<1>
  PIN Vs_b<1>
    DIRECTION INOUT ;
    USE SIGNAL ;
    PORT
      LAYER METAL2 ;
        RECT 24.5 0.0 25.75 0.61 ;
    END
  END Vs_b<1>
  PIN Vd_Pl<3>
    DIRECTION INOUT ;
    USE SIGNAL ;
    PORT
      LAYER METAL1 ;
        RECT 0.0 0.7 1.47 1.2 ;
    END
  END Vd_Pl<3>
  PIN Vd_Rl<3>
    DIRECTION INOUT ;
    USE SIGNAL ;
    PORT
      LAYER METAL1 ;
        RECT 0.0 3.5 1.45 4.0 ;
    END
  END Vd_Rl<3>
  PIN Vd_Rl<2>
    DIRECTION INOUT ;
    USE SIGNAL ;
    PORT
      LAYER METAL1 ;
        RECT 0.0 7.0 1.4 7.5 ;
    END
  END Vd_Rl<2>
  PIN Vd_Pl<2>
    DIRECTION INOUT ;
    USE SIGNAL ;
    PORT
      LAYER METAL1 ;
        RECT 0.0 9.8 1.41 10.3 ;
    END
  END Vd_Pl<2>
  PIN Vd_Pl<1>
    DIRECTION INOUT ;
    USE SIGNAL ;
    PORT
      LAYER METAL1 ;
        RECT 0.0 11.89 1.43 12.4 ;
    END
  END Vd_Pl<1>
  PIN Vd_Rl<1>
    DIRECTION INOUT ;
    USE SIGNAL ;
    PORT
      LAYER METAL1 ;
        RECT 0.0 14.7 1.46 15.2 ;
    END
  END Vd_Rl<1>
  PIN Vd_Rl<0>
    DIRECTION INOUT ;
    USE SIGNAL ;
    PORT
      LAYER METAL1 ;
        RECT 0.0 17.5 1.43 18.0 ;
    END
  END Vd_Rl<0>
  PIN Vd_Pl<0>
    DIRECTION INOUT ;
    USE SIGNAL ;
    PORT
      LAYER METAL1 ;
        RECT 0.0 20.3 1.4 20.9 ;
    END
  END Vd_Pl<0>
  PIN Vd_P<0>
    DIRECTION INOUT ;
    USE SIGNAL ;
    PORT
      LAYER METAL1 ;
        RECT 26.63 20.3 27.46 20.8 ;
    END
  END Vd_P<0>
  PIN Vd_R<1>
    DIRECTION INOUT ;
    USE SIGNAL ;
    PORT
      LAYER METAL1 ;
        RECT 26.56 14.7 27.44 15.2 ;
    END
  END Vd_R<1>
  PIN Vd_R<3>
    DIRECTION INOUT ;
    USE SIGNAL ;
    PORT
      LAYER METAL1 ;
        RECT 26.5 3.5 27.46 4.0 ;
    END
  END Vd_R<3>
  PIN Vd_P<3>
    DIRECTION INOUT ;
    USE SIGNAL ;
    PORT
      LAYER METAL1 ;
        RECT 26.55 0.7 27.46 1.2 ;
    END
  END Vd_P<3>
  PIN Vd_P<1>
    DIRECTION INOUT ;
    USE SIGNAL ;
    PORT
      LAYER METAL1 ;
        RECT 26.38 11.9 27.46 12.4 ;
    END
  END Vd_P<1>
  PIN Vd_P<2>
    DIRECTION INOUT ;
    USE SIGNAL ;
    PORT
      LAYER METAL1 ;
        RECT 26.51 9.8 27.46 10.3 ;
    END
  END Vd_P<2>
  PIN Vd_R<0>
    DIRECTION INOUT ;
    USE SIGNAL ;
    PORT
      LAYER METAL1 ;
        RECT 26.66 17.5 27.46 18.0 ;
    END
  END Vd_R<0>
  PIN Vd_R<2>
    DIRECTION INOUT ;
    USE SIGNAL ;
    PORT
      LAYER METAL1 ;
        RECT 26.53 7.0 27.46 7.5 ;
    END
  END Vd_R<2>
END TSMC350nm_4x2_Indirect

MACRO FNN_Relu_and_Sig
  PIN VTUN
    DIRECTION INOUT ;
    USE SIGNAL ;
    PORT
      LAYER METAL2 ;
        RECT 97.15 21.51 98.15 22.0 ;
    END
  END VTUN
  PIN Vin_p<0>
    DIRECTION INOUT ;
    USE SIGNAL ;
    PORT
      LAYER METAL2 ;
        RECT 0.0 12.23 0.44 13.23 ;
    END
  END Vin_p<0>
  PIN Vin_p<1>
    DIRECTION INOUT ;
    USE SIGNAL ;
    PORT
      LAYER METAL2 ;
        RECT 0.0 16.36 0.44 17.36 ;
    END
  END Vin_p<1>
  PIN Vin_m<1>
    DIRECTION INOUT ;
    USE SIGNAL ;
    PORT
      LAYER METAL2 ;
        RECT 0.0 14.23 0.44 15.23 ;
    END
  END Vin_m<1>
  PIN Vin_m<0>
    DIRECTION INOUT ;
    USE SIGNAL ;
    PORT
      LAYER METAL2 ;
        RECT 0.0 1.57 0.44 2.57 ;
    END
  END Vin_m<0>
  PIN VD_P<2>
    DIRECTION INOUT ;
    USE SIGNAL ;
    PORT
      LAYER METAL3 ;
        RECT 192.4 3.73 192.84 4.53 ;
    END
  END VD_P<2>
  PIN VD_P<1>
    DIRECTION INOUT ;
    USE SIGNAL ;
    PORT
      LAYER METAL3 ;
        RECT 192.4 9.62 192.84 10.42 ;
    END
  END VD_P<1>
  PIN VD_P<0>
    DIRECTION INOUT ;
    USE SIGNAL ;
    PORT
      LAYER METAL3 ;
        RECT 192.46 19.31 192.84 20.11 ;
    END
  END VD_P<0>
  PIN AVDD<1>
    DIRECTION INOUT ;
    USE SIGNAL ;
    PORT
      LAYER METAL2 ;
        RECT 189.99 21.57 190.99 22.0 ;
    END
  END AVDD<1>
  PIN Vg<1>
    DIRECTION INOUT ;
    USE SIGNAL ;
    PORT
      LAYER METAL2 ;
        RECT 128.82 21.57 129.62 22.0 ;
    END
  END Vg<1>
  PIN run
    DIRECTION INOUT ;
    USE SIGNAL ;
    PORT
      LAYER METAL2 ;
        RECT 67.84 21.57 68.64 22.0 ;
    END
  END run
  PIN prog
    DIRECTION INOUT ;
    USE SIGNAL ;
    PORT
      LAYER METAL2 ;
        RECT 62.61 21.57 63.41 22.0 ;
    END
  END prog
  PIN sel
    DIRECTION INOUT ;
    USE SIGNAL ;
    PORT
      LAYER METAL2 ;
        RECT 59.64 21.57 60.44 22.0 ;
    END
  END sel
  PIN Vg_bias
    DIRECTION INOUT ;
    USE SIGNAL ;
    PORT
      LAYER METAL2 ;
        RECT 57.76 21.57 58.56 22.0 ;
    END
  END Vg_bias
  PIN selb
    DIRECTION INOUT ;
    USE SIGNAL ;
    PORT
      LAYER METAL2 ;
        RECT 55.56 21.57 56.36 22.0 ;
    END
  END selb
  PIN Vsel<1>
    DIRECTION INOUT ;
    USE SIGNAL ;
    PORT
      LAYER METAL2 ;
        RECT 151.86 21.57 152.66 22.0 ;
    END
  END Vsel<1>
  PIN GND
    DIRECTION INOUT ;
    USE SIGNAL ;
    PORT
      LAYER METAL2 ;
        RECT 15.56 21.57 16.56 22.0 ;
    END
  END GND
  PIN VINJ
    DIRECTION INOUT ;
    USE SIGNAL ;
    PORT
      LAYER METAL2 ;
        RECT 39.69 21.57 40.59 22.0 ;
    END
  END VINJ
  PIN AVDD<0>
    DIRECTION INOUT ;
    USE SIGNAL ;
    PORT
      LAYER METAL2 ;
        RECT 4.29 21.57 5.29 22.0 ;
    END
  END AVDD<0>
  PIN Vsel<0>
    DIRECTION INOUT ;
    USE SIGNAL ;
    PORT
      LAYER METAL2 ;
        RECT 42.82 21.57 43.42 22.0 ;
    END
  END Vsel<0>
  PIN Vg<0>
    DIRECTION INOUT ;
    USE SIGNAL ;
    PORT
      LAYER METAL2 ;
        RECT 65.66 21.57 66.46 22.0 ;
    END
  END Vg<0>
  PIN Vsel_drt<1>
    DIRECTION INOUT ;
    USE SIGNAL ;
    PORT
      LAYER METAL2 ;
        RECT 109.58 21.57 110.38 22.0 ;
    END
  END Vsel_drt<1>
  PIN Vsel_drt<0>
    DIRECTION INOUT ;
    USE SIGNAL ;
    PORT
      LAYER METAL2 ;
        RECT 84.9 21.57 85.7 22.0 ;
    END
  END Vsel_drt<0>
  PIN Output<0>
    DIRECTION INOUT ;
    USE SIGNAL ;
    PORT
      LAYER METAL3 ;
        RECT 192.4 15.86 192.84 16.66 ;
    END
  END Output<0>
  PIN Output<1>
    DIRECTION INOUT ;
    USE SIGNAL ;
    PORT
      LAYER METAL3 ;
        RECT 192.4 12.01 192.84 12.81 ;
    END
  END Output<1>
END FNN_Relu_and_Sig

MACRO TSMC350nm_4WTA_IndirectProg_noncab
  PIN Vbias
    DIRECTION INOUT ;
    USE SIGNAL ;
    PORT
      LAYER METAL1 ;
        RECT 103.6 9.1 105.0 10.5 ;
    END
  END Vbias
  PIN Vmid
    DIRECTION INOUT ;
    USE SIGNAL ;
    PORT
      LAYER METAL1 ;
        RECT 103.6 13.3 105.0 14.7 ;
    END
  END Vmid
  PIN Vd_P<0>
    DIRECTION INOUT ;
    USE SIGNAL ;
    PORT
      LAYER METAL1 ;
        RECT 0.0 20.3 1.4 20.8 ;
    END
  END Vd_P<0>
  PIN Vd_P<1>
    DIRECTION INOUT ;
    USE SIGNAL ;
    PORT
      LAYER METAL1 ;
        RECT 0.0 11.9 1.4 12.4 ;
    END
  END Vd_P<1>
  PIN Vd_P<2>
    DIRECTION INOUT ;
    USE SIGNAL ;
    PORT
      LAYER METAL1 ;
        RECT 0.0 9.8 1.4 10.3 ;
    END
  END Vd_P<2>
  PIN Iin<1>
    DIRECTION INOUT ;
    USE SIGNAL ;
    PORT
      LAYER METAL1 ;
        RECT 0.0 14.7 1.4 15.2 ;
    END
  END Iin<1>
  PIN Vout<3>
    DIRECTION INOUT ;
    USE SIGNAL ;
    PORT
      LAYER METAL1 ;
        RECT 103.6 3.5 105.0 4.9 ;
    END
  END Vout<3>
  PIN Vd_P<3>
    DIRECTION INOUT ;
    USE SIGNAL ;
    PORT
      LAYER METAL1 ;
        RECT 0.0 0.7 1.4 1.2 ;
    END
  END Vd_P<3>
  PIN Iin<3>
    DIRECTION INOUT ;
    USE SIGNAL ;
    PORT
      LAYER METAL1 ;
        RECT 0.0 3.5 1.4 4.0 ;
    END
  END Iin<3>
  PIN Vout<2>
    DIRECTION INOUT ;
    USE SIGNAL ;
    PORT
      LAYER METAL1 ;
        RECT 103.6 6.3 105.0 7.7 ;
    END
  END Vout<2>
  PIN Iin<2>
    DIRECTION INOUT ;
    USE SIGNAL ;
    PORT
      LAYER METAL1 ;
        RECT 0.0 7.0 1.4 7.5 ;
    END
  END Iin<2>
  PIN Iin<0>
    DIRECTION INOUT ;
    USE SIGNAL ;
    PORT
      LAYER METAL1 ;
        RECT 0.0 17.5 1.4 18.0 ;
    END
  END Iin<0>
  PIN Vout<0>
    DIRECTION INOUT ;
    USE SIGNAL ;
    PORT
      LAYER METAL1 ;
        RECT 103.6 18.9 105.0 20.3 ;
    END
  END Vout<0>
  PIN Vout<1>
    DIRECTION INOUT ;
    USE SIGNAL ;
    PORT
      LAYER METAL1 ;
        RECT 103.6 16.1 105.0 17.5 ;
    END
  END Vout<1>
  PIN Vsel_b
    DIRECTION INOUT ;
    USE SIGNAL ;
    PORT
      LAYER METAL2 ;
        RECT 2.1 0.0 3.5 1.4 ;
    END
  END Vsel_b
  PIN GND
    DIRECTION INOUT ;
    USE SIGNAL ;
    PORT
      LAYER METAL2 ;
        RECT 17.5 20.6 18.9 22.0 ;
    END
  END GND
  PIN Vsel
    DIRECTION INOUT ;
    USE SIGNAL ;
    PORT
      LAYER METAL2 ;
        RECT 2.1 20.6 3.5 22.0 ;
    END
  END Vsel
  PIN GND_b
    DIRECTION INOUT ;
    USE SIGNAL ;
    PORT
      LAYER METAL2 ;
        RECT 17.5 0.0 18.9 1.4 ;
    END
  END GND_b
  PIN VTUN_b
    DIRECTION INOUT ;
    USE SIGNAL ;
    PORT
      LAYER METAL2 ;
        RECT 14.7 0.0 16.1 1.4 ;
    END
  END VTUN_b
  PIN VTUN
    DIRECTION INOUT ;
    USE SIGNAL ;
    PORT
      LAYER METAL2 ;
        RECT 14.7 20.6 16.1 22.0 ;
    END
  END VTUN
  PIN Vg
    DIRECTION INOUT ;
    USE SIGNAL ;
    PORT
      LAYER METAL2 ;
        RECT 11.9 20.6 13.3 22.0 ;
    END
  END Vg
  PIN Vs
    DIRECTION INOUT ;
    USE SIGNAL ;
    PORT
      LAYER METAL2 ;
        RECT 6.3 20.6 7.7 22.0 ;
    END
  END Vs
  PIN VINJ
    DIRECTION INOUT ;
    USE SIGNAL ;
    PORT
      LAYER METAL2 ;
        RECT 9.1 20.6 10.5 22.0 ;
    END
  END VINJ
  PIN PROG
    DIRECTION INOUT ;
    USE SIGNAL ;
    PORT
      LAYER METAL2 ;
        RECT 35.7 20.6 37.1 22.0 ;
    END
  END PROG
  PIN Vg_b
    DIRECTION INOUT ;
    USE SIGNAL ;
    PORT
      LAYER METAL2 ;
        RECT 11.9 0.0 13.3 1.4 ;
    END
  END Vg_b
  PIN Vs_b
    DIRECTION INOUT ;
    USE SIGNAL ;
    PORT
      LAYER METAL2 ;
        RECT 6.3 0.0 7.7 1.4 ;
    END
  END Vs_b
  PIN VINJ_b
    DIRECTION INOUT ;
    USE SIGNAL ;
    PORT
      LAYER METAL2 ;
        RECT 9.1 0.0 10.5 1.4 ;
    END
  END VINJ_b
  PIN PROG_b
    DIRECTION INOUT ;
    USE SIGNAL ;
    PORT
      LAYER METAL2 ;
        RECT 35.7 0.0 37.1 1.4 ;
    END
  END PROG_b
END TSMC350nm_4WTA_IndirectProg_noncab

MACRO FNN_DiodeConn
  PIN Vd_P_in<2>
    DIRECTION INOUT ;
    USE SIGNAL ;
    PORT
      LAYER METAL1 ;
        RECT 0.0 0.64 0.42 1.14 ;
    END
  END Vd_P_in<2>
  PIN Vd_P_in<1>
    DIRECTION INOUT ;
    USE SIGNAL ;
    PORT
      LAYER METAL1 ;
        RECT 0.0 9.59 0.42 10.09 ;
    END
  END Vd_P_in<1>
  PIN Vd_P_in<0>
    DIRECTION INOUT ;
    USE SIGNAL ;
    PORT
      LAYER METAL1 ;
        RECT 0.0 11.9 0.42 12.4 ;
    END
  END Vd_P_in<0>
  PIN Vd_R<3>
    DIRECTION INOUT ;
    USE SIGNAL ;
    PORT
      LAYER METAL1 ;
        RECT 0.0 3.3 0.42 4.0 ;
    END
  END Vd_R<3>
  PIN Vd_R<2>
    DIRECTION INOUT ;
    USE SIGNAL ;
    PORT
      LAYER METAL1 ;
        RECT 0.0 6.33 0.42 7.03 ;
    END
  END Vd_R<2>
  PIN Vd_R<1>
    DIRECTION INOUT ;
    USE SIGNAL ;
    PORT
      LAYER METAL1 ;
        RECT 0.0 14.5 0.42 15.2 ;
    END
  END Vd_R<1>
  PIN Vd_R<0>
    DIRECTION INOUT ;
    USE SIGNAL ;
    PORT
      LAYER METAL1 ;
        RECT 0.0 17.5 0.42 18.2 ;
    END
  END Vd_R<0>
  PIN Vd_P_out<0>
    DIRECTION INOUT ;
    USE SIGNAL ;
    PORT
      LAYER METAL2 ;
        RECT 189.95 19.21 190.37 20.21 ;
    END
  END Vd_P_out<0>
  PIN Vin_m<0>
    DIRECTION INOUT ;
    USE SIGNAL ;
    PORT
      LAYER METAL2 ;
        RECT 189.93 1.57 190.37 2.57 ;
    END
  END Vin_m<0>
  PIN Vd_P_out<2>
    DIRECTION INOUT ;
    USE SIGNAL ;
    PORT
      LAYER METAL2 ;
        RECT 189.93 3.62 190.37 4.62 ;
    END
  END Vd_P_out<2>
  PIN Vd_P_out<1>
    DIRECTION INOUT ;
    USE SIGNAL ;
    PORT
      LAYER METAL2 ;
        RECT 189.93 9.51 190.37 10.51 ;
    END
  END Vd_P_out<1>
  PIN Vin_p<0>
    DIRECTION INOUT ;
    USE SIGNAL ;
    PORT
      LAYER METAL2 ;
        RECT 189.93 12.23 190.37 13.23 ;
    END
  END Vin_p<0>
  PIN Vin_m<1>
    DIRECTION INOUT ;
    USE SIGNAL ;
    PORT
      LAYER METAL2 ;
        RECT 189.93 14.23 190.37 15.23 ;
    END
  END Vin_m<1>
  PIN Vin_p<1>
    DIRECTION INOUT ;
    USE SIGNAL ;
    PORT
      LAYER METAL2 ;
        RECT 189.93 16.36 190.37 17.36 ;
    END
  END Vin_p<1>
  PIN GND
    DIRECTION INOUT ;
    USE SIGNAL ;
    PORT
      LAYER METAL2 ;
        RECT 18.35 21.33 19.75 22.0 ;
    END
  END GND
  PIN RUN
    DIRECTION INOUT ;
    USE SIGNAL ;
    PORT
      LAYER METAL2 ;
        RECT 16.0 21.33 17.0 22.0 ;
    END
  END RUN
  PIN VINJ
    DIRECTION INOUT ;
    USE SIGNAL ;
    PORT
      LAYER METAL2 ;
        RECT 9.08 21.33 10.08 22.0 ;
    END
  END VINJ
  PIN PROG
    DIRECTION INOUT ;
    USE SIGNAL ;
    PORT
      LAYER METAL2 ;
        RECT 2.16 21.33 3.16 22.0 ;
    END
  END PROG
END FNN_DiodeConn

MACRO FakeCellGateDecoder
END FakeCellGateDecoder

END LIBRARY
